One B-rep face of a CAD part: STEP entity #208.
In plain terms, the planar face has unit normal (0, -1, 0).
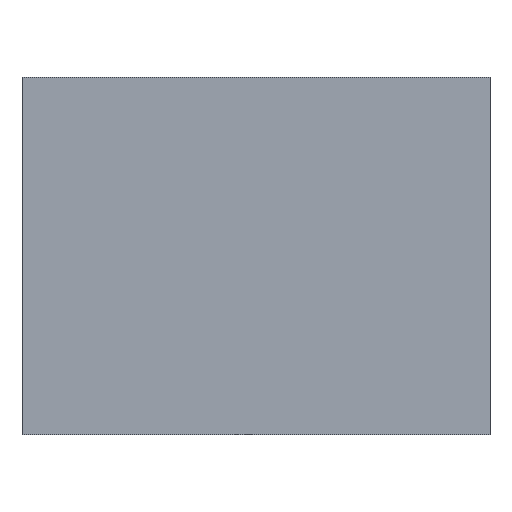
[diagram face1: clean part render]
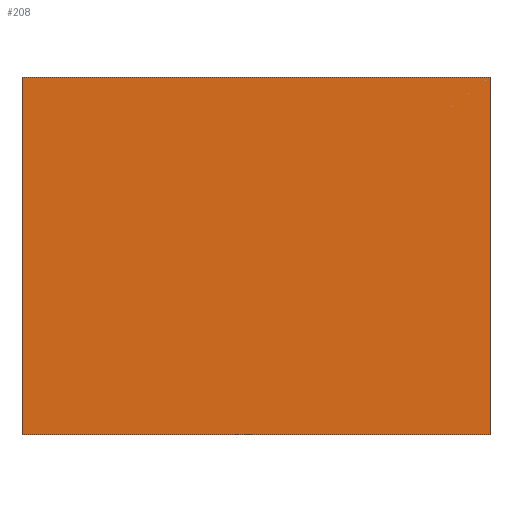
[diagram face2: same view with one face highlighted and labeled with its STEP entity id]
Its self-contained STEP definition (entity closure, numbers rounded to 3 decimals):
#208 = ADVANCED_FACE('',(#209),#223,.F.);
#209 = FACE_BOUND('',#210,.T.);
#210 = EDGE_LOOP('',(#211,#246,#274,#302));
#211 = ORIENTED_EDGE('',*,*,#212,.F.);
#212 = EDGE_CURVE('',#213,#215,#217,.T.);
#213 = VERTEX_POINT('',#214);
#214 = CARTESIAN_POINT('',(-17.,-49.599,-11.));
#215 = VERTEX_POINT('',#216);
#216 = CARTESIAN_POINT('',(17.,-49.599,-11.));
#217 = SURFACE_CURVE('',#218,(#222,#234),.PCURVE_S1.);
#218 = LINE('',#219,#220);
#219 = CARTESIAN_POINT('',(-17.,-49.599,-11.));
#220 = VECTOR('',#221,1.);
#221 = DIRECTION('',(1.,0.,0.));
#222 = PCURVE('',#223,#228);
#223 = PLANE('',#224);
#224 = AXIS2_PLACEMENT_3D('',#225,#226,#227);
#225 = CARTESIAN_POINT('',(-17.,-49.599,-37.));
#226 = DIRECTION('',(-0.,1.,0.));
#227 = DIRECTION('',(0.,0.,1.));
#228 = DEFINITIONAL_REPRESENTATION('',(#229),#233);
#229 = LINE('',#230,#231);
#230 = CARTESIAN_POINT('',(26.,0.));
#231 = VECTOR('',#232,1.);
#232 = DIRECTION('',(0.,1.));
#233 = ( GEOMETRIC_REPRESENTATION_CONTEXT(2) 
PARAMETRIC_REPRESENTATION_CONTEXT() REPRESENTATION_CONTEXT('2D SPACE',''
  ) );
#234 = PCURVE('',#235,#240);
#235 = PLANE('',#236);
#236 = AXIS2_PLACEMENT_3D('',#237,#238,#239);
#237 = CARTESIAN_POINT('',(-17.,-49.599,-11.));
#238 = DIRECTION('',(0.,0.,1.));
#239 = DIRECTION('',(1.,0.,-0.));
#240 = DEFINITIONAL_REPRESENTATION('',(#241),#245);
#241 = LINE('',#242,#243);
#242 = CARTESIAN_POINT('',(0.,0.));
#243 = VECTOR('',#244,1.);
#244 = DIRECTION('',(1.,0.));
#245 = ( GEOMETRIC_REPRESENTATION_CONTEXT(2) 
PARAMETRIC_REPRESENTATION_CONTEXT() REPRESENTATION_CONTEXT('2D SPACE',''
  ) );
#246 = ORIENTED_EDGE('',*,*,#247,.F.);
#247 = EDGE_CURVE('',#248,#213,#250,.T.);
#248 = VERTEX_POINT('',#249);
#249 = CARTESIAN_POINT('',(-17.,-49.599,-37.));
#250 = SURFACE_CURVE('',#251,(#255,#262),.PCURVE_S1.);
#251 = LINE('',#252,#253);
#252 = CARTESIAN_POINT('',(-17.,-49.599,-37.));
#253 = VECTOR('',#254,1.);
#254 = DIRECTION('',(0.,-0.,1.));
#255 = PCURVE('',#223,#256);
#256 = DEFINITIONAL_REPRESENTATION('',(#257),#261);
#257 = LINE('',#258,#259);
#258 = CARTESIAN_POINT('',(0.,0.));
#259 = VECTOR('',#260,1.);
#260 = DIRECTION('',(1.,0.));
#261 = ( GEOMETRIC_REPRESENTATION_CONTEXT(2) 
PARAMETRIC_REPRESENTATION_CONTEXT() REPRESENTATION_CONTEXT('2D SPACE',''
  ) );
#262 = PCURVE('',#263,#268);
#263 = PLANE('',#264);
#264 = AXIS2_PLACEMENT_3D('',#265,#266,#267);
#265 = CARTESIAN_POINT('',(-17.,-49.599,-37.));
#266 = DIRECTION('',(1.,0.,-0.));
#267 = DIRECTION('',(-0.,0.,-1.));
#268 = DEFINITIONAL_REPRESENTATION('',(#269),#273);
#269 = LINE('',#270,#271);
#270 = CARTESIAN_POINT('',(0.,0.));
#271 = VECTOR('',#272,1.);
#272 = DIRECTION('',(-1.,0.));
#273 = ( GEOMETRIC_REPRESENTATION_CONTEXT(2) 
PARAMETRIC_REPRESENTATION_CONTEXT() REPRESENTATION_CONTEXT('2D SPACE',''
  ) );
#274 = ORIENTED_EDGE('',*,*,#275,.F.);
#275 = EDGE_CURVE('',#276,#248,#278,.T.);
#276 = VERTEX_POINT('',#277);
#277 = CARTESIAN_POINT('',(17.,-49.599,-37.));
#278 = SURFACE_CURVE('',#279,(#283,#290),.PCURVE_S1.);
#279 = LINE('',#280,#281);
#280 = CARTESIAN_POINT('',(-17.,-49.599,-37.));
#281 = VECTOR('',#282,1.);
#282 = DIRECTION('',(-1.,-0.,-0.));
#283 = PCURVE('',#223,#284);
#284 = DEFINITIONAL_REPRESENTATION('',(#285),#289);
#285 = LINE('',#286,#287);
#286 = CARTESIAN_POINT('',(0.,0.));
#287 = VECTOR('',#288,1.);
#288 = DIRECTION('',(-0.,-1.));
#289 = ( GEOMETRIC_REPRESENTATION_CONTEXT(2) 
PARAMETRIC_REPRESENTATION_CONTEXT() REPRESENTATION_CONTEXT('2D SPACE',''
  ) );
#290 = PCURVE('',#291,#296);
#291 = PLANE('',#292);
#292 = AXIS2_PLACEMENT_3D('',#293,#294,#295);
#293 = CARTESIAN_POINT('',(-17.,-49.599,-37.));
#294 = DIRECTION('',(0.,0.,1.));
#295 = DIRECTION('',(1.,0.,-0.));
#296 = DEFINITIONAL_REPRESENTATION('',(#297),#301);
#297 = LINE('',#298,#299);
#298 = CARTESIAN_POINT('',(0.,0.));
#299 = VECTOR('',#300,1.);
#300 = DIRECTION('',(-1.,0.));
#301 = ( GEOMETRIC_REPRESENTATION_CONTEXT(2) 
PARAMETRIC_REPRESENTATION_CONTEXT() REPRESENTATION_CONTEXT('2D SPACE',''
  ) );
#302 = ORIENTED_EDGE('',*,*,#303,.F.);
#303 = EDGE_CURVE('',#215,#276,#304,.T.);
#304 = SURFACE_CURVE('',#305,(#309,#316),.PCURVE_S1.);
#305 = LINE('',#306,#307);
#306 = CARTESIAN_POINT('',(17.,-49.599,-37.));
#307 = VECTOR('',#308,1.);
#308 = DIRECTION('',(-0.,0.,-1.));
#309 = PCURVE('',#223,#310);
#310 = DEFINITIONAL_REPRESENTATION('',(#311),#315);
#311 = LINE('',#312,#313);
#312 = CARTESIAN_POINT('',(0.,34.));
#313 = VECTOR('',#314,1.);
#314 = DIRECTION('',(-1.,0.));
#315 = ( GEOMETRIC_REPRESENTATION_CONTEXT(2) 
PARAMETRIC_REPRESENTATION_CONTEXT() REPRESENTATION_CONTEXT('2D SPACE',''
  ) );
#316 = PCURVE('',#317,#322);
#317 = PLANE('',#318);
#318 = AXIS2_PLACEMENT_3D('',#319,#320,#321);
#319 = CARTESIAN_POINT('',(17.,-49.599,-37.));
#320 = DIRECTION('',(1.,0.,-0.));
#321 = DIRECTION('',(-0.,0.,-1.));
#322 = DEFINITIONAL_REPRESENTATION('',(#323),#327);
#323 = LINE('',#324,#325);
#324 = CARTESIAN_POINT('',(0.,0.));
#325 = VECTOR('',#326,1.);
#326 = DIRECTION('',(1.,0.));
#327 = ( GEOMETRIC_REPRESENTATION_CONTEXT(2) 
PARAMETRIC_REPRESENTATION_CONTEXT() REPRESENTATION_CONTEXT('2D SPACE',''
  ) );
